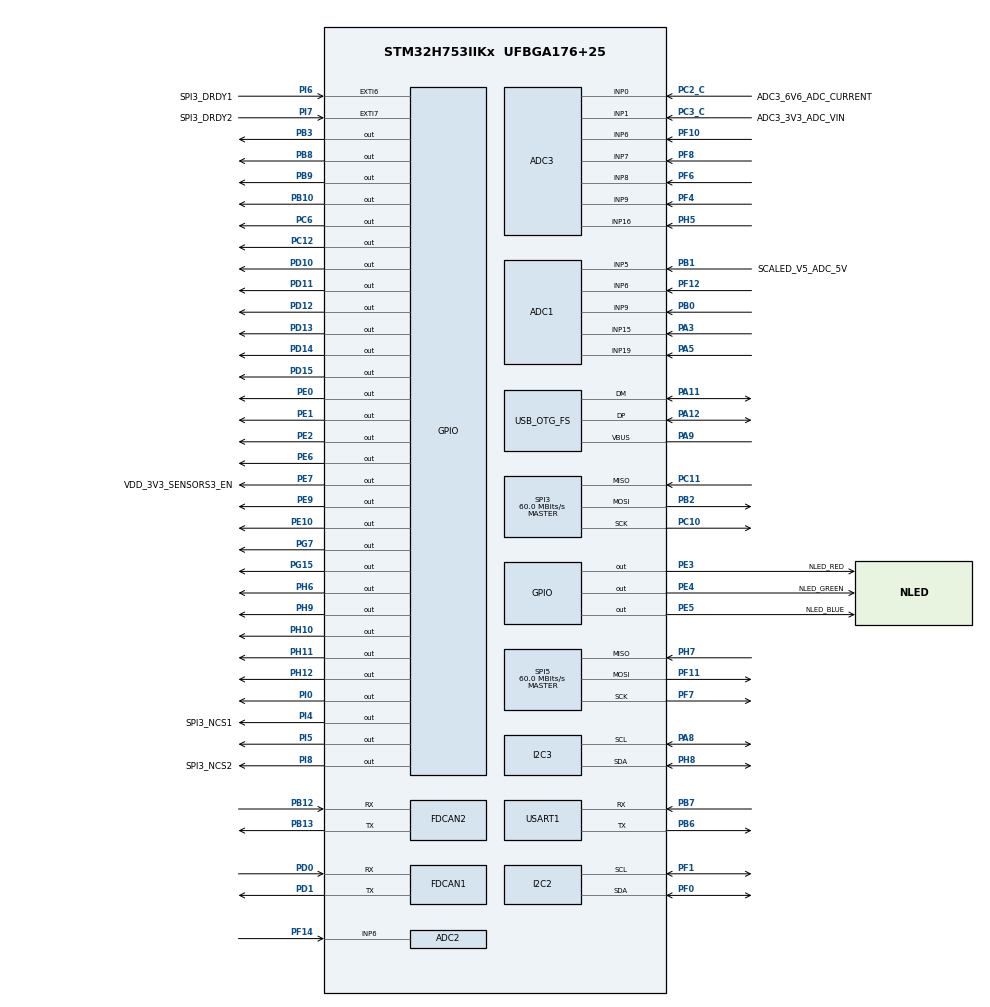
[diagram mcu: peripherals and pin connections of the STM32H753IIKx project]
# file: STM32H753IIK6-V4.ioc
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ADC1.Channel-6\#ChannelRegularConversion=ADC_CHANNEL_15
ADC1.ClockPrescaler=ADC_CLOCK_ASYNC_DIV4
ADC1.NbrOfConversionFlag=1
ADC1.OffsetNumber-6\#ChannelRegularConversion=ADC_OFFSET_NONE
ADC1.OffsetSignedSaturation-6\#ChannelRegularConversion=DISABLE
ADC1.Rank-6\#ChannelRegularConversion=1
ADC1.SamplingTime-6\#ChannelRegularConversion=ADC_SAMPLETIME_1CYCLE_5
ADC1.master=1
ADC2.Channel-1\#ChannelRegularConversion=ADC_CHANNEL_6
ADC2.ClockPrescaler=ADC_CLOCK_ASYNC_DIV4
ADC2.NbrOfConversionFlag=1
ADC2.OffsetNumber-1\#ChannelRegularConversion=ADC_OFFSET_NONE
ADC2.OffsetSignedSaturation-1\#ChannelRegularConversion=DISABLE
ADC2.Rank-1\#ChannelRegularConversion=1
ADC2.SamplingTime-1\#ChannelRegularConversion=ADC_SAMPLETIME_1CYCLE_5
ADC3.Channel-0\#ChannelRegularConversion=ADC_CHANNEL_0
ADC3.ClockPrescaler=ADC_CLOCK_ASYNC_DIV4
ADC3.NbrOfConversionFlag=1
ADC3.OffsetNumber-0\#ChannelRegularConversion=ADC_OFFSET_NONE
ADC3.OffsetSignedSaturation-0\#ChannelRegularConversion=DISABLE
ADC3.Rank-0\#ChannelRegularConversion=1
ADC3.SamplingTime-0\#ChannelRegularConversion=ADC_SAMPLETIME_1CYCLE_5
CORTEX_M7.default_mode_Activation=1
FDCAN1.AutoRetransmission=ENABLE
FDCAN1.CalculateBaudRateNominal=1000000
FDCAN1.CalculateTimeBitNominal=1000
FDCAN1.CalculateTimeQuantumNominal=100.0
FDCAN1.NominalPrescaler=12
FDCAN1.NominalTimeSeg1=7
FDCAN1.NominalTimeSeg2=2
FDCAN1.RxFifo0ElmtsNbr=16
FDCAN1.RxFifo1ElmtsNbr=1
FDCAN1.TransmitPause=ENABLE
FDCAN1.TxBuffersNbr=16
FDCAN1.TxFifoQueueElmtsNbr=16
FDCAN2.CalculateBaudRateNominal=2500000
FDCAN2.CalculateTimeBitNominal=400
FDCAN2.CalculateTimeQuantumNominal=133.33333333333334
FDCAN2.TxBuffersNbr=32
I2C2.Timing=0x307075B1
I2C3.Timing=0x307075B1
IWDG1.Prescaler=IWDG_PRESCALER_32
Mcu.Family=STM32H7
Mcu.Name=STM32H753IIKx
Mcu.Package=UFBGA176+25
NVIC.FDCAN1_IT0_IRQn=true\:0\:0\:false\:false\:true\:true\:true\:true
NVIC.OTG_FS_IRQn=true\:0\:0\:false\:false\:true\:false\:true\:true
NVIC.PriorityGroup=NVIC_PRIORITYGROUP_4
PA0.Signal=ADC1_INP16
PA1.Signal=ETH_REF_CLK
PA11.Mode=Device_Only
PA11.Signal=USB_OTG_FS_DM
PA12.Mode=Device_Only
PA12.Signal=USB_OTG_FS_DP
PA13\ (JTMS/SWDIO).Mode=Serial_Wire
PA13\ (JTMS/SWDIO).Signal=DEBUG_JTMS-SWDIO
PA14\ (JTCK/SWCLK).Mode=Serial_Wire
PA14\ (JTCK/SWCLK).Signal=DEBUG_JTCK-SWCLK
PA2.Signal=ETH_MDIO
PA3.Signal=ADCx_INP15
PA4.Signal=ADCx_INP18
PA5.Signal=ADCx_INP19
PA6.Signal=ADCx_INP3
PA7.Signal=ETH_CRS_DV
PA8.Mode=I2C
PA8.Signal=I2C3_SCL
PA9.Mode=Activate_VBUS
PA9.Signal=USB_OTG_FS_VBUS
PB0.Signal=ADCx_INP9
PB1.GPIO_Label=SCALED_V5_ADC_5V
PB1.Signal=ADCx_INP5
PB10.Signal=GPIO_Output
PB11.Signal=ETH_TX_EN
PB12.Mode=FDCAN_Activate
PB12.Signal=FDCAN2_RX
PB13.Mode=FDCAN_Activate
PB13.Signal=FDCAN2_TX
PB14.Signal=SDMMC2_D0
PB15.Signal=SDMMC2_D1
PB2.Mode=Full_Duplex_Master
PB2.Signal=SPI3_MOSI
PB3\ (JTDO/TRACESWO).Signal=GPIO_Output
PB6.Mode=Asynchronous
PB6.Signal=USART1_TX
PB7.Mode=Asynchronous
PB7.Signal=USART1_RX
PB8.Signal=GPIO_Output
PB9.Signal=GPIO_Output
PC0.Signal=ADCx_INP10
PC1.Signal=ETH_MDC
PC10.Mode=Full_Duplex_Master
PC10.Signal=SPI3_SCK
PC11.Mode=Full_Duplex_Master
PC11.Signal=SPI3_MISO
PC12.Signal=GPIO_Output
PC14-OSC32_IN\ (OSC32_IN).Mode=LSE-External-Oscillator
PC14-OSC32_IN\ (OSC32_IN).Signal=RCC_OSC32_IN
PC15-OSC32_OUT\ (OSC32_OUT).Mode=LSE-External-Oscillator
PC15-OSC32_OUT\ (OSC32_OUT).Signal=RCC_OSC32_OUT
PC2_C.GPIO_Label=ADC3_6V6_ADC_CURRENT
PC2_C.Mode=IN0-Single-Ended
PC2_C.Signal=ADC3_INP0
PC3_C.GPIO_Label=ADC3_3V3_ADC_VIN
PC3_C.Mode=IN1-Single-Ended
PC3_C.Signal=ADC3_INP1
PC4.Signal=ETH_RXD0
PC5.Signal=ETH_RXD1
PC6.Signal=GPIO_Output
PD0.Mode=FDCAN_Activate
PD0.Signal=FDCAN1_RX
PD1.Mode=FDCAN_Activate
PD1.Signal=FDCAN1_TX
PD10.Signal=GPIO_Output
PD11.Signal=GPIO_Output
PD12.Signal=GPIO_Output
PD13.Signal=GPIO_Output
PD14.Signal=GPIO_Output
PD15.Signal=GPIO_Output
PD6.Signal=SDMMC2_CK
PD7.Signal=SDMMC2_CMD
PE0.Signal=GPIO_Output
PE1.Signal=GPIO_Output
PE10.Signal=GPIO_Output
PE2.Signal=GPIO_Output
PE3.GPIO_Label=NLED_RED
PE3.Signal=GPIO_Output
PE4.GPIO_Label=NLED_GREEN
PE4.Signal=GPIO_Output
PE5.GPIO_Label=NLED_BLUE
PE5.Signal=GPIO_Output
PE6.Signal=GPIO_Output
PE7.GPIO_Label=VDD_3V3_SENSORS3_EN
PE7.Signal=GPIO_Output
PE9.Signal=GPIO_Output
PF0.Mode=I2C
PF0.Signal=I2C2_SDA
PF1.Mode=I2C
PF1.Signal=I2C2_SCL
PF10.Mode=IN6-Single-Ended
PF10.Signal=ADC3_INP6
PF11.Mode=Full_Duplex_Master
PF11.Signal=SPI5_MOSI
PF12.Mode=IN6-Single-Ended
PF12.Signal=ADC1_INP6
PF13.Signal=ADC2_INP2
PF14.Mode=IN6-Single-Ended
PF14.Signal=ADC2_INP6
PF3.Signal=ADC3_INP5
PF4.Mode=IN9-Single-Ended
PF4.Signal=ADC3_INP9
PF5.Signal=ADC3_INP4
PF6.Mode=IN8-Single-Ended
PF6.Signal=ADC3_INP8
PF7.Mode=Full_Duplex_Master
PF7.Signal=SPI5_SCK
PF8.Mode=IN7-Single-Ended
PF8.Signal=ADC3_INP7
PF9.Signal=ADC3_INP2
PG11.Signal=SDMMC2_D2
PG12.Signal=ETH_TXD1
PG13.Signal=ETH_TXD0
PG15.Signal=GPIO_Output
PG7.Signal=GPIO_Output
PH0-OSC_IN\ (PH0).Mode=HSE-External-Oscillator
PH0-OSC_IN\ (PH0).Signal=RCC_OSC_IN
PH1-OSC_OUT\ (PH1).Mode=HSE-External-Oscillator
PH1-OSC_OUT\ (PH1).Signal=RCC_OSC_OUT
PH10.Signal=GPIO_Output
PH11.Signal=GPIO_Output
PH12.Signal=GPIO_Output
PH3.Signal=ADC3_INP14
PH4.Signal=ADC3_INP15
PH5.Mode=IN16-Single-Ended
PH5.Signal=ADC3_INP16
PH6.Signal=GPIO_Output
PH7.Mode=Full_Duplex_Master
PH7.Signal=SPI5_MISO
PH8.Mode=I2C
PH8.Signal=I2C3_SDA
PH9.Signal=GPIO_Output
PI0.Signal=GPIO_Output
PI4.GPIO_Label=SPI3_NCS1
PI4.Signal=GPIO_Output
PI5.Signal=GPIO_Output
PI6.GPIO_Label=SPI3_DRDY1
PI6.Signal=GPXTI6
PI7.GPIO_Label=SPI3_DRDY2
PI7.Signal=GPXTI7
PI8.GPIO_Label=SPI3_NCS2
PI8.Signal=GPIO_Output
ProjectManager.HeapSize=0x200
ProjectManager.StackSize=0x400
ProjectManager.TargetToolchain=CMake
RCC.ADCFreq_Value=80000000
RCC.APB1Freq_Value=120000000
RCC.APB2Freq_Value=120000000
RCC.APB3Freq_Value=120000000
RCC.APB4Freq_Value=120000000
RCC.CortexFreq_Value=480000000
RCC.D1PPRE=RCC_APB3_DIV2
RCC.D2PPRE1=RCC_APB1_DIV2
RCC.D2PPRE2=RCC_APB2_DIV2
RCC.D3PPRE=RCC_APB4_DIV2
RCC.DIVM1=1
RCC.DIVM2=1
RCC.DIVN1=60
RCC.DIVN2=10
RCC.DIVQ1=8
RCC.HCLKFreq_Value=240000000
RCC.HPRE=RCC_HCLK_DIV2
RCC.HSE_VALUE=16000000
RCC.PLL2FRACN=0
RCC.PLL3FRACN=0
RCC.PLLFRACN=0
RCC.PLLSourceVirtual=RCC_PLLSOURCE_HSE
RCC.SYSCLKFreq_VALUE=480000000
RCC.SYSCLKSource=RCC_SYSCLKSOURCE_PLLCLK
RCC.SupplySource=PWR_LDO_SUPPLY
RCC.USBCLockSelection=RCC_USBCLKSOURCE_HSI48
RCC.USBFreq_Value=48000000
SH.ADCx_INP10.0=ADC1_INP10
SH.ADCx_INP15.0=ADC1_INP15,IN15-Single-Ended
SH.ADCx_INP18.0=ADC1_INP18
SH.ADCx_INP19.0=ADC1_INP19,IN19-Single-Ended
SH.ADCx_INP3.0=ADC1_INP3
SH.ADCx_INP5.0=ADC1_INP5,IN5-Single-Ended
SH.ADCx_INP9.0=ADC1_INP9,IN9-Single-Ended
SPI3.CalculateBaudRate=60.0 MBits/s
SPI3.Direction=SPI_DIRECTION_2LINES
SPI3.Mode=SPI_MODE_MASTER
SPI3.VirtualType=VM_MASTER
SPI5.BaudRatePrescaler=SPI_BAUDRATEPRESCALER_2
SPI5.CalculateBaudRate=60.0 MBits/s
SPI5.Direction=SPI_DIRECTION_2LINES
SPI5.Mode=SPI_MODE_MASTER
SPI5.VirtualType=VM_MASTER
USART1.VirtualMode-Asynchronous=VM_ASYNC
USB_DEVICE.CLASS_NAME_FS=CDC
USB_DEVICE.VirtualMode-CDC_FS=Cdc
USB_DEVICE.VirtualModeFS=Cdc_FS
USB_OTG_FS.VirtualMode=Device_Only
VP_ADC3_TempSens_Input.Mode=IN-TempSens
VP_IWDG1_VS_IWDG.Mode=IWDG_Activate
VP_MEMORYMAP_VS_MEMORYMAP.Mode=CurAppReg
VP_USB_DEVICE_VS_USB_DEVICE_CDC_FS.Mode=CDC_FS
board=custom

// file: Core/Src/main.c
/* USER CODE BEGIN Header */
/**
  ******************************************************************************
  * @file           : main.c
  * @brief          : Main program body
  ******************************************************************************
  * @attention
  *
  * Copyright (c) 2026 STMicroelectronics.
  * All rights reserved.
  *
  * This software is licensed under terms that can be found in the LICENSE file
  * in the root directory of this software component.
  * If no LICENSE file comes with this software, it is provided AS-IS.
  *
  ******************************************************************************
  */
/* USER CODE END Header */
#include "main.h"
#include "adc.h"
#include "fdcan.h"
#include "i2c.h"
#include "spi.h"
#include "usart.h"
#include "gpio.h"

/* USER CODE BEGIN Includes */
#include "application.hpp"
/* USER CODE END Includes */

void SystemClock_Config(void);
void PeriphCommonClock_Config(void);
static void MPU_Config(void);

int main(void)
{

  /* MPU Configuration--------------------------------------------------------*/
  MPU_Config();

  /* MCU Configuration--------------------------------------------------------*/

  /* Reset of all peripherals, Initializes the Flash interface and the Systick. */
  HAL_Init();

  /* USER CODE BEGIN Init */
  MX_GPIO_Init();

  /* USER CODE END Init */

  /* Configure the system clock */
  SystemClock_Config();

  /* Configure the peripherals common clocks */
  PeriphCommonClock_Config();

  /* Initialize all configured peripherals */
  MX_GPIO_Init();
  MX_FDCAN1_Init();
  MX_ADC1_Init();
  MX_ADC2_Init();
  MX_ADC3_Init();
  MX_SPI5_Init();
  MX_I2C2_Init();
  MX_I2C3_Init();
  MX_SPI3_Init();
  MX_USART1_UART_Init();
  MX_FDCAN2_Init();
  /* USER CODE BEGIN 2 */

  application_entry_point();

  /* USER CODE END 2 */

  /* Infinite loop */
  while (1)
  {

  }
}

void SystemClock_Config(void)
{
  RCC_OscInitTypeDef RCC_OscInitStruct = {0};
  RCC_ClkInitTypeDef RCC_ClkInitStruct = {0};

  /** Supply configuration update enable
  */
  HAL_PWREx_ConfigSupply(PWR_LDO_SUPPLY);

  /** Configure the main internal regulator output voltage
  */
  __HAL_PWR_VOLTAGESCALING_CONFIG(PWR_REGULATOR_VOLTAGE_SCALE3);

  while(!__HAL_PWR_GET_FLAG(PWR_FLAG_VOSRDY)) {}

  /** Initializes the RCC Oscillators according to the specified parameters
  * in the RCC_OscInitTypeDef structure.
  */
  RCC_OscInitStruct.OscillatorType = RCC_OSCILLATORTYPE_HSI;
  RCC_OscInitStruct.HSIState = RCC_HSI_DIV1;
  RCC_OscInitStruct.HSICalibrationValue = RCC_HSICALIBRATION_DEFAULT;
  RCC_OscInitStruct.PLL.PLLState = RCC_PLL_ON;
  RCC_OscInitStruct.PLL.PLLSource = RCC_PLLSOURCE_HSI;
  RCC_OscInitStruct.PLL.PLLM = 4;
  RCC_OscInitStruct.PLL.PLLN = 9;
  RCC_OscInitStruct.PLL.PLLP = 2;
  RCC_OscInitStruct.PLL.PLLQ = 3;
  RCC_OscInitStruct.PLL.PLLR = 2;
  RCC_OscInitStruct.PLL.PLLRGE = RCC_PLL1VCIRANGE_3;
  RCC_OscInitStruct.PLL.PLLVCOSEL = RCC_PLL1VCOMEDIUM;
  RCC_OscInitStruct.PLL.PLLFRACN = 3072;
  if (HAL_RCC_OscConfig(&RCC_OscInitStruct) != HAL_OK)
  {
    Error_Handler();
  }

  /** Initializes the CPU, AHB and APB buses clocks
  */
  RCC_ClkInitStruct.ClockType = RCC_CLOCKTYPE_HCLK|RCC_CLOCKTYPE_SYSCLK
                              |RCC_CLOCKTYPE_PCLK1|RCC_CLOCKTYPE_PCLK2
                              |RCC_CLOCKTYPE_D3PCLK1|RCC_CLOCKTYPE_D1PCLK1;
  RCC_ClkInitStruct.SYSCLKSource = RCC_SYSCLKSOURCE_PLLCLK;
  RCC_ClkInitStruct.SYSCLKDivider = RCC_SYSCLK_DIV1;
  RCC_ClkInitStruct.AHBCLKDivider = RCC_HCLK_DIV1;
  RCC_ClkInitStruct.APB3CLKDivider = RCC_APB3_DIV1;
  RCC_ClkInitStruct.APB1CLKDivider = RCC_APB1_DIV2;
  RCC_ClkInitStruct.APB2CLKDivider = RCC_APB2_DIV2;
  RCC_ClkInitStruct.APB4CLKDivider = RCC_APB4_DIV1;

  if (HAL_RCC_ClockConfig(&RCC_ClkInitStruct, FLASH_LATENCY_1) != HAL_OK)
  {
    Error_Handler();
  }
}

void PeriphCommonClock_Config(void)
{
  RCC_PeriphCLKInitTypeDef PeriphClkInitStruct = {0};

  /** Initializes the peripherals clock
  */
  PeriphClkInitStruct.PeriphClockSelection = RCC_PERIPHCLK_ADC;
  PeriphClkInitStruct.PLL2.PLL2M = 4;
  PeriphClkInitStruct.PLL2.PLL2N = 10;
  PeriphClkInitStruct.PLL2.PLL2P = 2;
  PeriphClkInitStruct.PLL2.PLL2Q = 2;
  PeriphClkInitStruct.PLL2.PLL2R = 2;
  PeriphClkInitStruct.PLL2.PLL2RGE = RCC_PLL2VCIRANGE_3;
  PeriphClkInitStruct.PLL2.PLL2VCOSEL = RCC_PLL2VCOMEDIUM;
  PeriphClkInitStruct.PLL2.PLL2FRACN = 0;
  PeriphClkInitStruct.AdcClockSelection = RCC_ADCCLKSOURCE_PLL2;
  if (HAL_RCCEx_PeriphCLKConfig(&PeriphClkInitStruct) != HAL_OK)
  {
    Error_Handler();
  }
}

 /* MPU Configuration */

void MPU_Config(void)
{
  MPU_Region_InitTypeDef MPU_InitStruct = {0};

  /* Disables the MPU */
  HAL_MPU_Disable();

  /** Initializes and configures the Region and the memory to be protected
  */
  MPU_InitStruct.Enable = MPU_REGION_ENABLE;
  MPU_InitStruct.Number = MPU_REGION_NUMBER0;
  MPU_InitStruct.BaseAddress = 0x0;
  MPU_InitStruct.Size = MPU_REGION_SIZE_4GB;
  MPU_InitStruct.SubRegionDisable = 0x87;
  MPU_InitStruct.TypeExtField = MPU_TEX_LEVEL0;
  MPU_InitStruct.AccessPermission = MPU_REGION_NO_ACCESS;
  MPU_InitStruct.DisableExec = MPU_INSTRUCTION_ACCESS_DISABLE;
  MPU_InitStruct.IsShareable = MPU_ACCESS_SHAREABLE;
  MPU_InitStruct.IsCacheable = MPU_ACCESS_NOT_CACHEABLE;
  MPU_InitStruct.IsBufferable = MPU_ACCESS_NOT_BUFFERABLE;

  HAL_MPU_ConfigRegion(&MPU_InitStruct);
  /* Enables the MPU */
  HAL_MPU_Enable(MPU_PRIVILEGED_DEFAULT);

}

void Error_Handler(void)
{
  /* USER CODE BEGIN Error_Handler_Debug */
  /* User can add his own implementation to report the HAL error return state */
  __disable_irq();
  while (1)
  {
#if defined(NLED_RED_GPIO_Port) && defined(NLED_GREEN_GPIO_Port) && defined(NLED_BLUE_GPIO_Port)
    HAL_GPIO_WritePin(NLED_GREEN_GPIO_Port, NLED_GREEN_Pin, GPIO_PIN_SET);
    HAL_GPIO_WritePin(NLED_BLUE_GPIO_Port, NLED_BLUE_Pin, GPIO_PIN_SET);
    HAL_GPIO_WritePin(NLED_RED_GPIO_Port, NLED_RED_Pin, GPIO_PIN_RESET);
#endif
  }
  /* USER CODE END Error_Handler_Debug */
}
